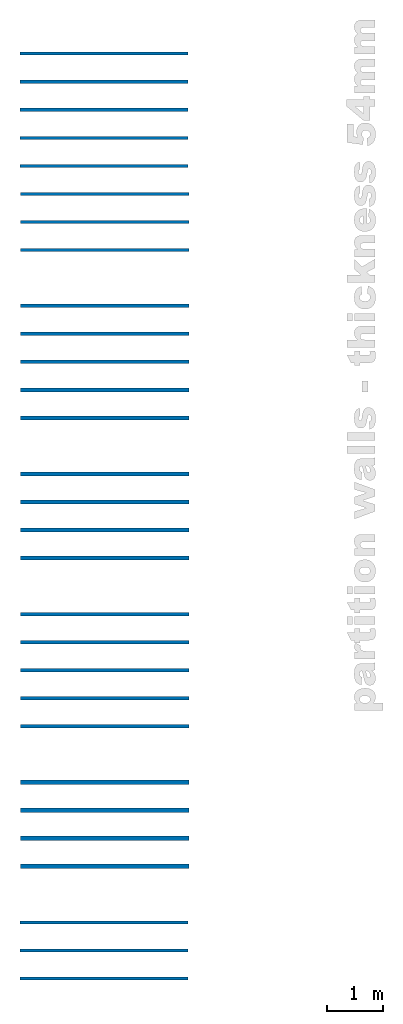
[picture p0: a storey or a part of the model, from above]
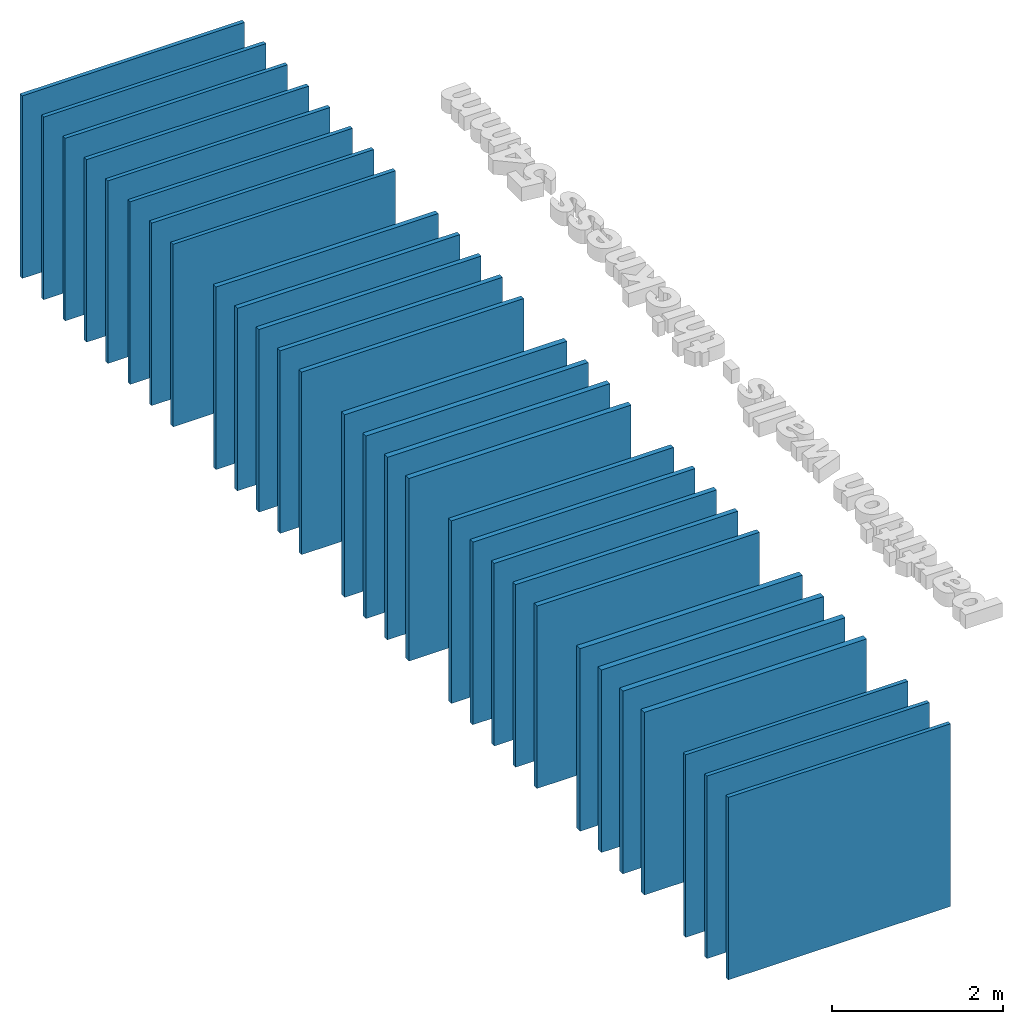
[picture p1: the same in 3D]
Properties of the parts of a building model (IFC2X3)

# File
Description: ViewDefinition [CoordinationView]
File name: 2344
Time: 2015-08-26T14:51:35
Written by: The EXPRESS Data Manager Version 5.02.0100.07 : 28 Aug 2013
Made in: 20140223_1515(x64) - Exporter 2015.0.2014.0223 - Default UI
Comment: STEP Physical File produced by: The EXPRESS Data Manager Version 5.02.0100.07 : 28 Aug 2013 * Module: EDMstepFileFactory/EDMstandAlone * Creation date: Wed Aug 26 14:51:35 2015 * Host: WKS-037 * Database: C:\Users\Alfons\AppData\Local\Temp\{7DC093A0-7D50-469D-A9C3-01EB25B16758}\ifc * Database version: 5507 * Database creation date: Wed Aug 26 14:51:34 2015 * Schema: IFC2X3 * Model: DataRepository.ifc * Model creation date: Wed Aug 26 14:51:34 2015 * Header model: DataRepository.ifc_HeaderModel * Header model creation date: Wed Aug 26 14:51:34 2015 * EDMuser: sdai-user * EDMgroup: sdai-group * License ID and type: 5605 : Permanent license. Expiry date: * EDMstepFileFactory options: 020000

# IfcProject, 2344
LongName: Project Name; Phase: DO

# IfcSite, Default
RefLatitude: 42, 21, 30, 344238; RefLongitude: -71, -3, -35, -194702; RefElevation: 0 mm
Other - Category: Project Information; Client Name: Owner; Project Address: Enter address here; Project Issue Date: Issue Date; Project Name: Project Name; Project Number: 2344; Project Status: DO

# IfcBuilding
Pset_BuildingCommon - NumberOfStoreys: 1
Other - Category: Project Information; Client Name: Owner; Project Address: Enter address here; Project Issue Date: Issue Date; Project Name: Project Name; Project Number: 2344; Project Status: DO

# IfcBuildingStorey, faay_bottom_view_color
LongName: faay_bottom_view_color; Elevation: 0 mm
Constraints - Elevation: 0 mm; Elevation Base: Project Base Point
Dimensions - Computation Height: 0 mm
Identity Data - Structural: no; Building Story: yes; Name: faay_bottom_view_color; Type Name: 8mm Head
Other - Category: Levels; Family: Level: 8mm Head; Family and Type: Level: 8mm Head; Type: Level: 8mm Head; Type Id: Level: 8mm Head; Family Name: Level
Graphics - Color: 0; Line Pattern: Centre; Line Weight: 1; Symbol: M_Level Head - Circle: M_Level Head - Circle; Symbol at End 1 Default: no; Symbol at End 2 Default: yes

# IfcBuildingElementProxy: Model Text:500 Arial Black
In: faay_bottom_view_color
Pset_BuildingElementProxyCommon - Reference: 500 Arial Black
Constraints - Work Plane: Level : faay_bottom_view_color
Dimensions - Depth: 200 mm
Graphics - Horizontal Align: Right; Text: partition walls - thickness 54mm
Identity Data - Subcategory: Generic Models; Type Name: 500 Arial Black
Other - Category: Generic Models; Family: Model Text: 500 Arial Black; Family and Type: Model Text: 500 Arial Black; Type: Model Text: 500 Arial Black; Type Id: Model Text: 500 Arial Black; Family Name: Model Text
Phasing - Phase Created: New Construction
Text - Bold: no; Italic: no; Text Font: Arial Black; Text Size: 500 mm

# IfcWallStandardCase: Basic Wall:Faay_22_RV54_, Basic Wall:Faay_22_RV54_:177242
In: faay_bottom_view_color
Type - PredefinedType: STANDARD; Material: faay_Rigidur 10 mm, faay_flax 34 mm, faay_Rigidur 10 mm
Type - Analytical Properties - Roughness: 1; Absorptance: 0.1
Type - Construction - Function: Exterior; Wrapping at Inserts: Do not wrap; Width: 54 mm
Type - Graphics - Coarse Scale Fill Color: 0
Type - Identity Data - Manufacturer: Faay Vianen B.V.; Model: Faay_22_RV54_; Type Name: Faay_22_RV54_; URL: http://http://www.faay.nl
Type - Other - Category: Walls; Family Name: Basic Wall
Type - Text - faay_avarage_labour_time_(mh/m2): 0.20; faay_fire_resistance_rating: >45 min.WBDBO; faay_heat_insulation_(Rc): 0.49; faay_sound_insulation_(DnTak): 26; faay_sound_insulation_(Rw): 27; faay_weight_(kg/m2): 23.85
Constraints - Base Constraint: Level: faay_bottom_view_color; Base Extension Distance: 0 mm; Base is Attached: no; Base Offset: 0 mm; Location Line: Wall Centerline; Related to Mass: no; Room Bounding: yes; Top Extension Distance: 0 mm; Top is Attached: no; Top Offset: 0 mm; Unconnected Height: 2605 mm
Dimensions - Area: 7.815 m2; Length: 3000 mm; Volume: 0.42201 m3
Other - Family: Basic Wall: Faay_22_RV54_; Family and Type: Basic Wall: Faay_22_RV54_; Type: Basic Wall: Faay_22_RV54_; Type Id: Basic Wall: Faay_22_RV54_
Phasing - Phase Created: New Construction
Structural - Enable Analytical Model: no; Structural: no; Structural Usage: Non-bearing
Pset_WallCommon - LoadBearing: no; ExtendToStructure: no; IsExternal: yes; Reference: Faay_22_RV54_
Pset_ManufacturerTypeInformation - Manufacturer: Faay Vianen B.V.

# IfcWallStandardCase: Basic Wall:Faay_22_SP54_, Basic Wall:Faay_22_SP54_:177233
In: faay_bottom_view_color
Type - PredefinedType: STANDARD; Material: faay_chipboard 10 mm, faay_flax 34 mm, faay_chipboard 10 mm
Type - Analytical Properties - Roughness: 1; Absorptance: 0.1
Type - Construction - Function: Exterior; Wrapping at Inserts: Do not wrap; Width: 54 mm
Type - Graphics - Coarse Scale Fill Color: 0
Type - Identity Data - Manufacturer: Faay Vianen B.V.; Model: Faay_22_SP54_; Type Name: Faay_22_SP54_; URL: http://http://www.faay.nl
Type - Other - Category: Walls; Family Name: Basic Wall
Type - Text - faay_avarage_labour_time_(mh/m2): 0.20; faay_fire_resistance_rating: <20 min.WBDBO; faay_heat_insulation_(Rc): 0.49; faay_sound_insulation_(DnTak): 24; faay_sound_insulation_(Rw): 27; faay_weight_(kg/m2): 23.85
Constraints - Base Constraint: Level: faay_bottom_view_color; Base Extension Distance: 0 mm; Base is Attached: no; Base Offset: 0 mm; Location Line: Wall Centerline; Related to Mass: no; Room Bounding: yes; Top Extension Distance: 0 mm; Top is Attached: no; Top Offset: 0 mm; Unconnected Height: 2605 mm
Dimensions - Area: 7.815 m2; Length: 3000 mm; Volume: 0.42201 m3
Other - Family: Basic Wall: Faay_22_SP54_; Family and Type: Basic Wall: Faay_22_SP54_; Type: Basic Wall: Faay_22_SP54_; Type Id: Basic Wall: Faay_22_SP54_
Phasing - Phase Created: New Construction
Structural - Enable Analytical Model: no; Structural: no; Structural Usage: Non-bearing
Pset_WallCommon - LoadBearing: no; ExtendToStructure: no; IsExternal: yes; Reference: Faay_22_SP54_
Pset_ManufacturerTypeInformation - Manufacturer: Faay Vianen B.V.

# IfcWallStandardCase: Basic Wall:Faay_22_SP54_Fo, Basic Wall:Faay_22_SP54_Fo:177236
In: faay_bottom_view_color
Type - PredefinedType: STANDARD; Material: faay_chipboard 10 mm, faay_flax 34 mm, faay_chipboard 10 mm
Type - Analytical Properties - Roughness: 1; Absorptance: 0.1
Type - Construction - Function: Exterior; Wrapping at Inserts: Do not wrap; Width: 54 mm
Type - Graphics - Coarse Scale Fill Color: 0
Type - Identity Data - Manufacturer: Faay Vianen B.V.; Model: Faay_22_SP54_F; Type Name: Faay_22_SP54_Fo; URL: http://http://www.faay.nl
Type - Other - Category: Walls; Family Name: Basic Wall
Type - Text - faay_avarage_labour_time_(mh/m2): 0.20; faay_fire_resistance_rating: <20 min.WBDBO; faay_heat_insulation_(Rc): 0.49; faay_sound_insulation_(DnTak): 24; faay_sound_insulation_(Rw): 27; faay_weight_(kg/m2): 23.85
Constraints - Base Constraint: Level: faay_bottom_view_color; Base Extension Distance: 0 mm; Base is Attached: no; Base Offset: 0 mm; Location Line: Wall Centerline; Related to Mass: no; Room Bounding: yes; Top Extension Distance: 0 mm; Top is Attached: no; Top Offset: 0 mm; Unconnected Height: 2605 mm
Dimensions - Area: 7.815 m2; Length: 3000 mm; Volume: 0.42201 m3
Other - Family: Basic Wall: Faay_22_SP54_Fo; Family and Type: Basic Wall: Faay_22_SP54_Fo; Type: Basic Wall: Faay_22_SP54_Fo; Type Id: Basic Wall: Faay_22_SP54_Fo
Phasing - Phase Created: New Construction
Structural - Enable Analytical Model: no; Structural: no; Structural Usage: Non-bearing
Pset_WallCommon - LoadBearing: no; ExtendToStructure: no; IsExternal: yes; Reference: Faay_22_SP54_Fo
Pset_ManufacturerTypeInformation - Manufacturer: Faay Vianen B.V.

# IfcWallStandardCase: Basic Wall:Faay_22_VP54_, Basic Wall:Faay_22_VP54_:177173
In: faay_bottom_view_color
Type - PredefinedType: STANDARD; Material: faay_gypsum 10 mm, faay_flax 34 mm, faay_gypsum 10 mm
Type - Analytical Properties - Roughness: 1; Absorptance: 0.1
Type - Construction - Function: Exterior; Wrapping at Inserts: Do not wrap; Width: 54 mm
Type - Graphics - Coarse Scale Fill Color: 7013078
Type - Identity Data - Manufacturer: Faay Vianen B.V.; Model: Faay_22_VP54_; Type Name: Faay_22_VP54_; URL: http://http://www.faay.nl
Type - Other - Category: Walls; Family Name: Basic Wall
Type - Text - faay_avarage_labour_time_(mh/m2): 0.20; faay_fire_resistance_rating: EI30; faay_heat_insulation_(Rc): 0.42; faay_sound_insulation_(DnTak): 29; faay_sound_insulation_(Rw): 30; faay_weight_(kg/m2): 38.12
Constraints - Base Constraint: Level: faay_bottom_view_color; Base Extension Distance: 0 mm; Base is Attached: no; Base Offset: 0 mm; Location Line: Wall Centerline; Related to Mass: no; Room Bounding: yes; Top Extension Distance: 0 mm; Top is Attached: no; Top Offset: 0 mm; Unconnected Height: 2605 mm
Dimensions - Area: 7.815 m2; Length: 3000 mm; Volume: 0.42201 m3
Other - Family: Basic Wall: Faay_22_VP54_; Family and Type: Basic Wall: Faay_22_VP54_; Type: Basic Wall: Faay_22_VP54_; Type Id: Basic Wall: Faay_22_VP54_
Phasing - Phase Created: New Construction
Structural - Enable Analytical Model: no; Structural: no; Structural Usage: Non-bearing
Pset_WallCommon - LoadBearing: no; ExtendToStructure: no; IsExternal: yes; Reference: Faay_22_VP54_
Pset_ManufacturerTypeInformation - Manufacturer: Faay Vianen B.V.

# IfcWallStandardCase: Basic Wall:Faay_22_VP54_10_1_B, Basic Wall:Faay_22_VP54_10_1_B:822858
In: faay_bottom_view_color
Type - PredefinedType: STANDARD; Material: faay_gypsum 10 mm, faay_gypsum 10 mm, faay_flax 34 mm, faay_gypsum 10 mm
Type - Analytical Properties - Roughness: 1; Absorptance: 0.1
Type - Construction - Function: Exterior; Wrapping at Inserts: Do not wrap; Width: 64 mm
Type - Graphics - Coarse Scale Fill Color: 0
Type - Identity Data - Manufacturer: Faay Vianen B.V.; Model: Faay_22_VP54_10_1; Type Name: Faay_22_VP54_10_1_B; URL: http://http://www.faay.nl
Type - Other - Category: Walls; Family Name: Basic Wall
Type - Text - faay_avarage_labour_time_(mh/m2): 0.33; faay_fire_resistance_rating: >60 min. WBDBO; faay_heat_insulation_(Rc): 0.45; faay_sound_insulation_(DnTak): 34; faay_sound_insulation_(Rw): 35; faay_weight_(kg/m2): 36.12
Constraints - Base Constraint: Level: faay_bottom_view_color; Base Extension Distance: 0 mm; Base is Attached: no; Base Offset: 0 mm; Location Line: Wall Centerline; Related to Mass: no; Room Bounding: yes; Top Extension Distance: 0 mm; Top is Attached: no; Top Offset: 0 mm; Unconnected Height: 2605 mm
Dimensions - Area: 7.815 m2; Length: 3000 mm; Volume: 0.50016 m3
Other - Family: Basic Wall: Faay_22_VP54_10_1_B; Family and Type: Basic Wall: Faay_22_VP54_10_1_B; Type: Basic Wall: Faay_22_VP54_10_1_B; Type Id: Basic Wall: Faay_22_VP54_10_1_B
Phasing - Phase Created: New Construction
Structural - Enable Analytical Model: no; Structural: no; Structural Usage: Non-bearing
Pset_WallCommon - LoadBearing: no; ExtendToStructure: no; IsExternal: yes; Reference: Faay_22_VP54_10_1_B
Pset_ManufacturerTypeInformation - Manufacturer: Faay Vianen B.V.

# IfcWallStandardCase: Basic Wall:Faay_22_VP54_10_1_F, Basic Wall:Faay_22_VP54_10_1_F:177185
In: faay_bottom_view_color
Type - PredefinedType: STANDARD; Material: faay_gypsum 10 mm, faay_flax 34 mm, faay_gypsum 10 mm, faay_gypsum 10 mm
Type - Analytical Properties - Roughness: 1; Absorptance: 0.1
Type - Construction - Function: Exterior; Wrapping at Inserts: Do not wrap; Width: 64 mm
Type - Graphics - Coarse Scale Fill Color: 0
Type - Identity Data - Manufacturer: Faay Vianen B.V.; Model: Faay_22_VP54_10_1; Type Name: Faay_22_VP54_10_1_F; URL: http://http://www.faay.nl
Type - Other - Category: Walls; Family Name: Basic Wall
Type - Text - faay_avarage_labour_time_(mh/m2): 0.33; faay_fire_resistance_rating: >60 min. WBDBO; faay_heat_insulation_(Rc): 0.45; faay_sound_insulation_(DnTak): 34; faay_sound_insulation_(Rw): 35; faay_weight_(kg/m2): 36.12
Constraints - Base Constraint: Level: faay_bottom_view_color; Base Extension Distance: 0 mm; Base is Attached: no; Base Offset: 0 mm; Location Line: Wall Centerline; Related to Mass: no; Room Bounding: yes; Top Extension Distance: 0 mm; Top is Attached: no; Top Offset: 0 mm; Unconnected Height: 2605 mm
Dimensions - Area: 7.815 m2; Length: 3000 mm; Volume: 0.50016 m3
Other - Family: Basic Wall: Faay_22_VP54_10_1_F; Family and Type: Basic Wall: Faay_22_VP54_10_1_F; Type: Basic Wall: Faay_22_VP54_10_1_F; Type Id: Basic Wall: Faay_22_VP54_10_1_F
Phasing - Phase Created: New Construction
Structural - Enable Analytical Model: no; Structural: no; Structural Usage: Non-bearing
Pset_WallCommon - LoadBearing: no; ExtendToStructure: no; IsExternal: yes; Reference: Faay_22_VP54_10_1_F
Pset_ManufacturerTypeInformation - Manufacturer: Faay Vianen B.V.

# IfcWallStandardCase: Basic Wall:Faay_22_VP54_10_1_WR1x_B, Basic Wall:Faay_22_VP54_10_1_WR1x_B:817365
In: faay_bottom_view_color
Type - PredefinedType: STANDARD; Material: faay_gypsum_WR 10 mm, faay_gypsum 10 mm, faay_flax 34 mm, faay_gypsum 10 mm
Type - Analytical Properties - Roughness: 1; Absorptance: 0.1
Type - Construction - Function: Exterior; Wrapping at Inserts: Do not wrap; Width: 64 mm
Type - Graphics - Coarse Scale Fill Color: 0
Type - Identity Data - Manufacturer: Faay Vianen B.V.; Model: Faay_22_VP54_10_1_WR1x_B; Type Name: Faay_22_VP54_10_1_WR1x_B; URL: http://http://www.faay.nl
Type - Other - Category: Walls; Family Name: Basic Wall
Type - Text - faay_avarage_labour_time_(mh/m2): 0.33; faay_fire_resistance_rating: >60 min. WBDBO; faay_heat_insulation_(Rc): 0.45; faay_sound_insulation_(DnTak): 34; faay_sound_insulation_(Rw): 35; faay_weight_(kg/m2): 36.12
Constraints - Base Constraint: Level: faay_bottom_view_color; Base Extension Distance: 0 mm; Base is Attached: no; Base Offset: 0 mm; Location Line: Wall Centerline; Related to Mass: no; Room Bounding: yes; Top Extension Distance: 0 mm; Top is Attached: no; Top Offset: 0 mm; Unconnected Height: 2605 mm
Dimensions - Area: 7.815 m2; Length: 3000 mm; Volume: 0.50016 m3
Other - Family: Basic Wall: Faay_22_VP54_10_1_WR1x_B; Family and Type: Basic Wall: Faay_22_VP54_10_1_WR1x_B; Type: Basic Wall: Faay_22_VP54_10_1_WR1x_B; Type Id: Basic Wall: Faay_22_VP54_10_1_WR1x_B
Phasing - Phase Created: New Construction
Structural - Enable Analytical Model: no; Structural: no; Structural Usage: Non-bearing
Pset_WallCommon - LoadBearing: no; ExtendToStructure: no; IsExternal: yes; Reference: Faay_22_VP54_10_1_WR1x_B
Pset_ManufacturerTypeInformation - Manufacturer: Faay Vianen B.V.

# IfcWallStandardCase: Basic Wall:Faay_22_VP54_10_1_WR1x_F, Basic Wall:Faay_22_VP54_10_1_WR1x_F:177184
In: faay_bottom_view_color
Type - PredefinedType: STANDARD; Material: faay_gypsum 10 mm, faay_flax 34 mm, faay_gypsum 10 mm, faay_gypsum_WR 10 mm
Type - Analytical Properties - Roughness: 1; Absorptance: 0.1
Type - Construction - Function: Exterior; Wrapping at Inserts: Do not wrap; Width: 64 mm
Type - Graphics - Coarse Scale Fill Color: 0
Type - Identity Data - Manufacturer: Faay Vianen B.V.; Model: Faay_22_VP54_10_1_WR1x_F; Type Name: Faay_22_VP54_10_1_WR1x_F; URL: http://http://www.faay.nl
Type - Other - Category: Walls; Family Name: Basic Wall
Type - Text - faay_avarage_labour_time_(mh/m2): 0.33; faay_fire_resistance_rating: >60 min. WBDBO; faay_heat_insulation_(Rc): 0.45; faay_sound_insulation_(DnTak): 34; faay_sound_insulation_(Rw): 35; faay_weight_(kg/m2): 36.12
Constraints - Base Constraint: Level: faay_bottom_view_color; Base Extension Distance: 0 mm; Base is Attached: no; Base Offset: 0 mm; Location Line: Wall Centerline; Related to Mass: no; Room Bounding: yes; Top Extension Distance: 0 mm; Top is Attached: no; Top Offset: 0 mm; Unconnected Height: 2605 mm
Dimensions - Area: 7.815 m2; Length: 3000 mm; Volume: 0.50016 m3
Other - Family: Basic Wall: Faay_22_VP54_10_1_WR1x_F; Family and Type: Basic Wall: Faay_22_VP54_10_1_WR1x_F; Type: Basic Wall: Faay_22_VP54_10_1_WR1x_F; Type Id: Basic Wall: Faay_22_VP54_10_1_WR1x_F
Phasing - Phase Created: New Construction
Structural - Enable Analytical Model: no; Structural: no; Structural Usage: Non-bearing
Pset_WallCommon - LoadBearing: no; ExtendToStructure: no; IsExternal: yes; Reference: Faay_22_VP54_10_1_WR1x_F
Pset_ManufacturerTypeInformation - Manufacturer: Faay Vianen B.V.

# IfcWallStandardCase: Basic Wall:Faay_22_VP54_10_1_WR2x, Basic Wall:Faay_22_VP54_10_1_WR2x:177183
In: faay_bottom_view_color
Type - PredefinedType: STANDARD; Material: faay_gypsum_WR 10 mm, faay_flax 34 mm, faay_gypsum 10 mm, faay_gypsum_WR 10 mm
Type - Analytical Properties - Roughness: 1; Absorptance: 0.1
Type - Construction - Function: Exterior; Wrapping at Inserts: Do not wrap; Width: 64 mm
Type - Graphics - Coarse Scale Fill Color: 0
Type - Identity Data - Manufacturer: Faay Vianen B.V.; Model: Faay_22_VP54_10_1_WR2x; Type Name: Faay_22_VP54_10_1_WR2x; URL: http://http://www.faay.nl
Type - Other - Category: Walls; Family Name: Basic Wall
Type - Text - faay_avarage_labour_time_(mh/m2): 0.33; faay_fire_resistance_rating: >60 min. WBDBO; faay_heat_insulation_(Rc): 0.45; faay_sound_insulation_(DnTak): 34; faay_sound_insulation_(Rw): 35; faay_weight_(kg/m2): 36.12
Constraints - Base Constraint: Level: faay_bottom_view_color; Base Extension Distance: 0 mm; Base is Attached: no; Base Offset: 0 mm; Location Line: Wall Centerline; Related to Mass: no; Room Bounding: yes; Top Extension Distance: 0 mm; Top is Attached: no; Top Offset: 0 mm; Unconnected Height: 2605 mm
Dimensions - Area: 7.815 m2; Length: 3000 mm; Volume: 0.50016 m3
Other - Family: Basic Wall: Faay_22_VP54_10_1_WR2x; Family and Type: Basic Wall: Faay_22_VP54_10_1_WR2x; Type: Basic Wall: Faay_22_VP54_10_1_WR2x; Type Id: Basic Wall: Faay_22_VP54_10_1_WR2x
Phasing - Phase Created: New Construction
Structural - Enable Analytical Model: no; Structural: no; Structural Usage: Non-bearing
Pset_WallCommon - LoadBearing: no; ExtendToStructure: no; IsExternal: yes; Reference: Faay_22_VP54_10_1_WR2x
Pset_ManufacturerTypeInformation - Manufacturer: Faay Vianen B.V.

# IfcWallStandardCase: Basic Wall:Faay_22_VP54_10_2_, Basic Wall:Faay_22_VP54_10_2_:177207
In: faay_bottom_view_color
Type - PredefinedType: STANDARD; Material: faay_gypsum 10 mm, faay_gypsum 10 mm, faay_flax 34 mm, faay_gypsum 10 mm, faay_gypsum 10 mm
Type - Analytical Properties - Roughness: 1; Absorptance: 0.1
Type - Construction - Function: Exterior; Wrapping at Inserts: Do not wrap; Width: 74 mm
Type - Graphics - Coarse Scale Fill Color: 0
Type - Identity Data - Manufacturer: Faay Vianen B.V.; Model: Faay_22_VP54_10_2; Type Name: Faay_22_VP54_10_2_; URL: http://http://www.faay.nl
Type - Other - Category: Walls; Family Name: Basic Wall
Type - Text - faay_avarage_labour_time_(mh/m2): 0.46; faay_fire_resistance_rating: >60 min. WBDBO; faay_heat_insulation_(Rc): 0.49; faay_sound_insulation_(DnTak): 35; faay_sound_insulation_(Rw): 36; faay_weight_(kg/m2): 44.12
Constraints - Base Constraint: Level: faay_bottom_view_color; Base Extension Distance: 0 mm; Base is Attached: no; Base Offset: 0 mm; Location Line: Wall Centerline; Related to Mass: no; Room Bounding: yes; Top Extension Distance: 0 mm; Top is Attached: no; Top Offset: 0 mm; Unconnected Height: 2605 mm
Dimensions - Area: 7.815 m2; Length: 3000 mm; Volume: 0.57831 m3
Other - Family: Basic Wall: Faay_22_VP54_10_2_; Family and Type: Basic Wall: Faay_22_VP54_10_2_; Type: Basic Wall: Faay_22_VP54_10_2_; Type Id: Basic Wall: Faay_22_VP54_10_2_
Phasing - Phase Created: New Construction
Structural - Enable Analytical Model: no; Structural: no; Structural Usage: Non-bearing
Pset_WallCommon - LoadBearing: no; ExtendToStructure: no; IsExternal: yes; Reference: Faay_22_VP54_10_2_
Pset_ManufacturerTypeInformation - Manufacturer: Faay Vianen B.V.

# IfcWallStandardCase: Basic Wall:Faay_22_VP54_10_2_WR1x_B, Basic Wall:Faay_22_VP54_10_2_WR1x_B:177206
In: faay_bottom_view_color
Type - PredefinedType: STANDARD; Material: faay_gypsum_WR 10 mm, faay_gypsum 10 mm, faay_flax 34 mm, faay_gypsum 10 mm, faay_gypsum 10 mm
Type - Analytical Properties - Roughness: 1; Absorptance: 0.1
Type - Construction - Function: Exterior; Wrapping at Inserts: Do not wrap; Width: 74 mm
Type - Graphics - Coarse Scale Fill Color: 0
Type - Identity Data - Manufacturer: Faay Vianen B.V.; Model: Faay_22_VP54_10_2_WR1x_B; Type Name: Faay_22_VP54_10_2_WR1x_B; URL: http://http://www.faay.nl
Type - Other - Category: Walls; Family Name: Basic Wall
Type - Text - faay_avarage_labour_time_(mh/m2): 0.46; faay_fire_resistance_rating: >60 min. WBDBO; faay_heat_insulation_(Rc): 0.49; faay_sound_insulation_(DnTak): 35; faay_sound_insulation_(Rw): 36; faay_weight_(kg/m2): 44.12
Constraints - Base Constraint: Level: faay_bottom_view_color; Base Extension Distance: 0 mm; Base is Attached: no; Base Offset: 0 mm; Location Line: Wall Centerline; Related to Mass: no; Room Bounding: yes; Top Extension Distance: 0 mm; Top is Attached: no; Top Offset: 0 mm; Unconnected Height: 2605 mm
Dimensions - Area: 7.815 m2; Length: 3000 mm; Volume: 0.57831 m3
Other - Family: Basic Wall: Faay_22_VP54_10_2_WR1x_B; Family and Type: Basic Wall: Faay_22_VP54_10_2_WR1x_B; Type: Basic Wall: Faay_22_VP54_10_2_WR1x_B; Type Id: Basic Wall: Faay_22_VP54_10_2_WR1x_B
Phasing - Phase Created: New Construction
Structural - Enable Analytical Model: no; Structural: no; Structural Usage: Non-bearing
Pset_WallCommon - LoadBearing: no; ExtendToStructure: no; IsExternal: yes; Reference: Faay_22_VP54_10_2_WR1x_B
Pset_ManufacturerTypeInformation - Manufacturer: Faay Vianen B.V.

# IfcWallStandardCase: Basic Wall:Faay_22_VP54_10_2_WR1x_F, Basic Wall:Faay_22_VP54_10_2_WR1x_F:817162
In: faay_bottom_view_color
Type - PredefinedType: STANDARD; Material: faay_gypsum 10 mm, faay_gypsum 10 mm, faay_flax 34 mm, faay_gypsum 10 mm, faay_gypsum_WR 10 mm
Type - Analytical Properties - Roughness: 1; Absorptance: 0.1
Type - Construction - Function: Exterior; Wrapping at Inserts: Do not wrap; Width: 74 mm
Type - Graphics - Coarse Scale Fill Color: 0
Type - Identity Data - Manufacturer: Faay Vianen B.V.; Model: Faay_22_VP54_10_2_WR1x_F; Type Name: Faay_22_VP54_10_2_WR1x_F; URL: http://http://www.faay.nl
Type - Other - Category: Walls; Family Name: Basic Wall
Type - Text - faay_avarage_labour_time_(mh/m2): 0.46; faay_fire_resistance_rating: >60 min. WBDBO; faay_heat_insulation_(Rc): 0.49; faay_sound_insulation_(DnTak): 35; faay_sound_insulation_(Rw): 36; faay_weight_(kg/m2): 44.12
Constraints - Base Constraint: Level: faay_bottom_view_color; Base Extension Distance: 0 mm; Base is Attached: no; Base Offset: 0 mm; Location Line: Wall Centerline; Related to Mass: no; Room Bounding: yes; Top Extension Distance: 0 mm; Top is Attached: no; Top Offset: 0 mm; Unconnected Height: 2605 mm
Dimensions - Area: 7.815 m2; Length: 3000 mm; Volume: 0.57831 m3
Other - Family: Basic Wall: Faay_22_VP54_10_2_WR1x_F; Family and Type: Basic Wall: Faay_22_VP54_10_2_WR1x_F; Type: Basic Wall: Faay_22_VP54_10_2_WR1x_F; Type Id: Basic Wall: Faay_22_VP54_10_2_WR1x_F
Phasing - Phase Created: New Construction
Structural - Enable Analytical Model: no; Structural: no; Structural Usage: Non-bearing
Pset_WallCommon - LoadBearing: no; ExtendToStructure: no; IsExternal: yes; Reference: Faay_22_VP54_10_2_WR1x_F
Pset_ManufacturerTypeInformation - Manufacturer: Faay Vianen B.V.

# IfcWallStandardCase: Basic Wall:Faay_22_VP54_10_2_WR2x, Basic Wall:Faay_22_VP54_10_2_WR2x:177212
In: faay_bottom_view_color
Type - PredefinedType: STANDARD; Material: faay_gypsum_WR 10 mm, faay_gypsum 10 mm, faay_flax 34 mm, faay_gypsum 10 mm, faay_gypsum_WR 10 mm
Type - Analytical Properties - Roughness: 1; Absorptance: 0.1
Type - Construction - Function: Exterior; Wrapping at Inserts: Do not wrap; Width: 74 mm
Type - Graphics - Coarse Scale Fill Color: 0
Type - Identity Data - Manufacturer: Faay Vianen B.V.; Model: Faay_22_VP54_10_2_WR2x; Type Name: Faay_22_VP54_10_2_WR2x; URL: http://http://www.faay.nl
Type - Other - Category: Walls; Family Name: Basic Wall
Type - Text - faay_avarage_labour_time_(mh/m2): 0.46; faay_fire_resistance_rating: >60 min. WBDBO; faay_heat_insulation_(Rc): 0.49; faay_sound_insulation_(DnTak): 35; faay_sound_insulation_(Rw): 36; faay_weight_(kg/m2): 44.12
Constraints - Base Constraint: Level: faay_bottom_view_color; Base Extension Distance: 0 mm; Base is Attached: no; Base Offset: 0 mm; Location Line: Wall Centerline; Related to Mass: no; Room Bounding: yes; Top Extension Distance: 0 mm; Top is Attached: no; Top Offset: 0 mm; Unconnected Height: 2605 mm
Dimensions - Area: 7.815 m2; Length: 3000 mm; Volume: 0.57831 m3
Other - Family: Basic Wall: Faay_22_VP54_10_2_WR2x; Family and Type: Basic Wall: Faay_22_VP54_10_2_WR2x; Type: Basic Wall: Faay_22_VP54_10_2_WR2x; Type Id: Basic Wall: Faay_22_VP54_10_2_WR2x
Phasing - Phase Created: New Construction
Structural - Enable Analytical Model: no; Structural: no; Structural Usage: Non-bearing
Pset_WallCommon - LoadBearing: no; ExtendToStructure: no; IsExternal: yes; Reference: Faay_22_VP54_10_2_WR2x
Pset_ManufacturerTypeInformation - Manufacturer: Faay Vianen B.V.

# IfcWallStandardCase: Basic Wall:Faay_22_VP54_12.5_1_B, Basic Wall:Faay_22_VP54_12.5_1_B:825457
In: faay_bottom_view_color
Type - PredefinedType: STANDARD; Material: faay_gypsum 12.5 mm, faay_gypsum 10 mm, faay_flax 34 mm, faay_gypsum 10 mm
Type - Analytical Properties - Roughness: 1; Absorptance: 0.1
Type - Construction - Function: Exterior; Wrapping at Inserts: Do not wrap; Width: 66.5 mm
Type - Graphics - Coarse Scale Fill Color: 0
Type - Identity Data - Manufacturer: Faay Vianen B.V.; Model: Faay_22_VP54_12.5_1; Type Name: Faay_22_VP54_12.5_1_B; URL: http://http://www.faay.nl
Type - Other - Category: Walls; Family Name: Basic Wall
Type - Text - faay_avarage_labour_time_(mh/m2): 0.33; faay_fire_resistance_rating: >60 min. WBDBO; faay_heat_insulation_(Rc): 0.45; faay_sound_insulation_(DnTak): 34; faay_sound_insulation_(Rw): 35; faay_weight_(kg/m2): 38.92
Constraints - Base Constraint: Level: faay_bottom_view_color; Base Extension Distance: 0 mm; Base is Attached: no; Base Offset: 0 mm; Location Line: Wall Centerline; Related to Mass: no; Room Bounding: yes; Top Extension Distance: 0 mm; Top is Attached: no; Top Offset: 0 mm; Unconnected Height: 2605 mm
Dimensions - Area: 7.815 m2; Length: 3000 mm; Volume: 0.519698 m3
Other - Family: Basic Wall: Faay_22_VP54_12.5_1_B; Family and Type: Basic Wall: Faay_22_VP54_12.5_1_B; Type: Basic Wall: Faay_22_VP54_12.5_1_B; Type Id: Basic Wall: Faay_22_VP54_12.5_1_B
Phasing - Phase Created: New Construction
Structural - Enable Analytical Model: no; Structural: no; Structural Usage: Non-bearing
Pset_WallCommon - LoadBearing: no; ExtendToStructure: no; IsExternal: yes; Reference: Faay_22_VP54_12.5_1_B
Pset_ManufacturerTypeInformation - Manufacturer: Faay Vianen B.V.

# IfcWallStandardCase: Basic Wall:Faay_22_VP54_12.5_1_F, Basic Wall:Faay_22_VP54_12.5_1_F:177217
In: faay_bottom_view_color
Type - PredefinedType: STANDARD; Material: faay_gypsum 10 mm, faay_flax 34 mm, faay_gypsum 10 mm, faay_gypsum 12.5 mm
Type - Analytical Properties - Roughness: 1; Absorptance: 0.1
Type - Construction - Function: Exterior; Wrapping at Inserts: Do not wrap; Width: 66.5 mm
Type - Graphics - Coarse Scale Fill Color: 0
Type - Identity Data - Manufacturer: Faay Vianen B.V.; Model: Faay_22_VP54_12.5_1; Type Name: Faay_22_VP54_12.5_1_F; URL: http://http://www.faay.nl
Type - Other - Category: Walls; Family Name: Basic Wall
Type - Text - faay_avarage_labour_time_(mh/m2): 0.33; faay_fire_resistance_rating: >60 min. WBDBO; faay_heat_insulation_(Rc): 0.45; faay_sound_insulation_(DnTak): 34; faay_sound_insulation_(Rw): 35; faay_weight_(kg/m2): 38.92
Constraints - Base Constraint: Level: faay_bottom_view_color; Base Extension Distance: 0 mm; Base is Attached: no; Base Offset: 0 mm; Location Line: Wall Centerline; Related to Mass: no; Room Bounding: yes; Top Extension Distance: 0 mm; Top is Attached: no; Top Offset: 0 mm; Unconnected Height: 2605 mm
Dimensions - Area: 7.815 m2; Length: 3000 mm; Volume: 0.519698 m3
Other - Family: Basic Wall: Faay_22_VP54_12.5_1_F; Family and Type: Basic Wall: Faay_22_VP54_12.5_1_F; Type: Basic Wall: Faay_22_VP54_12.5_1_F; Type Id: Basic Wall: Faay_22_VP54_12.5_1_F
Phasing - Phase Created: New Construction
Structural - Enable Analytical Model: no; Structural: no; Structural Usage: Non-bearing
Pset_WallCommon - LoadBearing: no; ExtendToStructure: no; IsExternal: yes; Reference: Faay_22_VP54_12.5_1_F
Pset_ManufacturerTypeInformation - Manufacturer: Faay Vianen B.V.

# IfcWallStandardCase: Basic Wall:Faay_22_VP54_12.5_1_WR1x_B, Basic Wall:Faay_22_VP54_12.5_1_WR1x_B:177216
In: faay_bottom_view_color
Type - PredefinedType: STANDARD; Material: faay_gypsum_WR 10 mm, faay_flax 34 mm, faay_gypsum 10 mm, faay_gypsum 12.5 mm
Type - Analytical Properties - Roughness: 1; Absorptance: 0.1
Type - Construction - Function: Exterior; Wrapping at Inserts: Do not wrap; Width: 66.5 mm
Type - Graphics - Coarse Scale Fill Color: 0
Type - Identity Data - Manufacturer: Faay Vianen B.V.; Model: Faay_22_VP54_12.5_1_WR1x_B; Type Name: Faay_22_VP54_12.5_1_WR1x_B; URL: http://http://www.faay.nl
Type - Other - Category: Walls; Family Name: Basic Wall
Type - Text - faay_avarage_labour_time_(mh/m2): 0.33; faay_fire_resistance_rating: >60 min. WBDBO; faay_heat_insulation_(Rc): 0.45; faay_sound_insulation_(DnTak): 34; faay_sound_insulation_(Rw): 35; faay_weight_(kg/m2): 38.92
Constraints - Base Constraint: Level: faay_bottom_view_color; Base Extension Distance: 0 mm; Base is Attached: no; Base Offset: 0 mm; Location Line: Wall Centerline; Related to Mass: no; Room Bounding: yes; Top Extension Distance: 0 mm; Top is Attached: no; Top Offset: 0 mm; Unconnected Height: 2605 mm
Dimensions - Area: 7.815 m2; Length: 3000 mm; Volume: 0.519697 m3
Other - Family: Basic Wall: Faay_22_VP54_12.5_1_WR1x_B; Family and Type: Basic Wall: Faay_22_VP54_12.5_1_WR1x_B; Type: Basic Wall: Faay_22_VP54_12.5_1_WR1x_B; Type Id: Basic Wall: Faay_22_VP54_12.5_1_WR1x_B
Phasing - Phase Created: New Construction
Structural - Enable Analytical Model: no; Structural: no; Structural Usage: Non-bearing
Pset_WallCommon - LoadBearing: no; ExtendToStructure: no; IsExternal: yes; Reference: Faay_22_VP54_12.5_1_WR1x_B
Pset_ManufacturerTypeInformation - Manufacturer: Faay Vianen B.V.

# IfcWallStandardCase: Basic Wall:Faay_22_VP54_12.5_1_WR1x_F, Basic Wall:Faay_22_VP54_12.5_1_WR1x_F:817574
In: faay_bottom_view_color
Type - PredefinedType: STANDARD; Material: faay_gypsum 12.5 mm, faay_gypsum 10 mm, faay_flax 34 mm, faay_gypsum_WR 10 mm
Type - Analytical Properties - Roughness: 1; Absorptance: 0.1
Type - Construction - Function: Exterior; Wrapping at Inserts: Do not wrap; Width: 66.5 mm
Type - Graphics - Coarse Scale Fill Color: 0
Type - Identity Data - Manufacturer: Faay Vianen B.V.; Model: Faay_22_VP54_12.5_1_WR1x_F; Type Name: Faay_22_VP54_12.5_1_WR1x_F; URL: http://http://www.faay.nl
Type - Other - Category: Walls; Family Name: Basic Wall
Type - Text - faay_avarage_labour_time_(mh/m2): 0.33; faay_fire_resistance_rating: >60 min. WBDBO; faay_heat_insulation_(Rc): 0.45; faay_sound_insulation_(DnTak): 34; faay_sound_insulation_(Rw): 35; faay_weight_(kg/m2): 38.92
Constraints - Base Constraint: Level: faay_bottom_view_color; Base Extension Distance: 0 mm; Base is Attached: no; Base Offset: 0 mm; Location Line: Wall Centerline; Related to Mass: no; Room Bounding: yes; Top Extension Distance: 0 mm; Top is Attached: no; Top Offset: 0 mm; Unconnected Height: 2605 mm
Dimensions - Area: 7.815 m2; Length: 3000 mm; Volume: 0.519697 m3
Other - Family: Basic Wall: Faay_22_VP54_12.5_1_WR1x_F; Family and Type: Basic Wall: Faay_22_VP54_12.5_1_WR1x_F; Type: Basic Wall: Faay_22_VP54_12.5_1_WR1x_F; Type Id: Basic Wall: Faay_22_VP54_12.5_1_WR1x_F
Phasing - Phase Created: New Construction
Structural - Enable Analytical Model: no; Structural: no; Structural Usage: Non-bearing
Pset_WallCommon - LoadBearing: no; ExtendToStructure: no; IsExternal: yes; Reference: Faay_22_VP54_12.5_1_WR1x_F
Pset_ManufacturerTypeInformation - Manufacturer: Faay Vianen B.V.

# IfcWallStandardCase: Basic Wall:Faay_22_VP54_12.5_1_WR2x, Basic Wall:Faay_22_VP54_12.5_1_WR2x:177215
In: faay_bottom_view_color
Type - PredefinedType: STANDARD; Material: faay_gypsum_WR 10 mm, faay_flax 34 mm, faay_gypsum 10 mm, faay_gypsum_WR 12.5 mm
Type - Analytical Properties - Roughness: 1; Absorptance: 0.1
Type - Construction - Function: Exterior; Wrapping at Inserts: Do not wrap; Width: 66.5 mm
Type - Graphics - Coarse Scale Fill Color: 0
Type - Identity Data - Manufacturer: Faay Vianen B.V.; Model: Faay_22_VP54_12.5_1_WR2x; Type Name: Faay_22_VP54_12.5_1_WR2x; URL: http://http://www.faay.nl
Type - Other - Category: Walls; Family Name: Basic Wall
Type - Text - faay_avarage_labour_time_(mh/m2): 0.33; faay_fire_resistance_rating: >60 min. WBDBO; faay_heat_insulation_(Rc): 0.45; faay_sound_insulation_(DnTak): 34; faay_sound_insulation_(Rw): 35; faay_weight_(kg/m2): 38.92
Constraints - Base Constraint: Level: faay_bottom_view_color; Base Extension Distance: 0 mm; Base is Attached: no; Base Offset: 0 mm; Location Line: Wall Centerline; Related to Mass: no; Room Bounding: yes; Top Extension Distance: 0 mm; Top is Attached: no; Top Offset: 0 mm; Unconnected Height: 2605 mm
Dimensions - Area: 7.815 m2; Length: 3000 mm; Volume: 0.519697 m3
Other - Family: Basic Wall: Faay_22_VP54_12.5_1_WR2x; Family and Type: Basic Wall: Faay_22_VP54_12.5_1_WR2x; Type: Basic Wall: Faay_22_VP54_12.5_1_WR2x; Type Id: Basic Wall: Faay_22_VP54_12.5_1_WR2x
Phasing - Phase Created: New Construction
Structural - Enable Analytical Model: no; Structural: no; Structural Usage: Non-bearing
Pset_WallCommon - LoadBearing: no; ExtendToStructure: no; IsExternal: yes; Reference: Faay_22_VP54_12.5_1_WR2x
Pset_ManufacturerTypeInformation - Manufacturer: Faay Vianen B.V.

# IfcWallStandardCase: Basic Wall:Faay_22_VP54_12.5_2_, Basic Wall:Faay_22_VP54_12.5_2_:832891
In: faay_bottom_view_color
Type - PredefinedType: STANDARD; Material: faay_gypsum 12.5 mm, faay_gypsum 10 mm, faay_flax 34 mm, faay_gypsum 10 mm, faay_gypsum 12.5 mm
Type - Analytical Properties - Roughness: 1; Absorptance: 0.1
Type - Construction - Function: Exterior; Wrapping at Inserts: Do not wrap; Width: 79 mm
Type - Graphics - Coarse Scale Fill Color: 0
Type - Identity Data - Manufacturer: Faay Vianen B.V.; Model: Faay_22_VP54_12.5_2; Type Name: Faay_22_VP54_12.5_2_; URL: http://http://www.faay.nl
Type - Other - Category: Walls; Family Name: Basic Wall
Type - Text - faay_avarage_labour_time_(mh/m2): 0.46; faay_fire_resistance_rating: >60 min. WBDBO; faay_heat_insulation_(Rc): 0.65; faay_sound_insulation_(DnTak): 34; faay_sound_insulation_(Rw): 35; faay_weight_(kg/m2): 49.72
Constraints - Base Constraint: Level: faay_bottom_view_color; Base Extension Distance: 0 mm; Base is Attached: no; Base Offset: 0 mm; Location Line: Wall Centerline; Related to Mass: no; Room Bounding: yes; Top Extension Distance: 0 mm; Top is Attached: no; Top Offset: 0 mm; Unconnected Height: 2605 mm
Dimensions - Area: 7.815 m2; Length: 3000 mm; Volume: 0.617385 m3
Other - Family: Basic Wall: Faay_22_VP54_12.5_2_; Family and Type: Basic Wall: Faay_22_VP54_12.5_2_; Type: Basic Wall: Faay_22_VP54_12.5_2_; Type Id: Basic Wall: Faay_22_VP54_12.5_2_
Phasing - Phase Created: New Construction
Structural - Enable Analytical Model: no; Structural: no; Structural Usage: Non-bearing
Pset_WallCommon - LoadBearing: no; ExtendToStructure: no; IsExternal: yes; Reference: Faay_22_VP54_12.5_2_
Pset_ManufacturerTypeInformation - Manufacturer: Faay Vianen B.V.

# IfcWallStandardCase: Basic Wall:Faay_22_VP54_12.5_2_WR1x_B, Basic Wall:Faay_22_VP54_12.5_2_WR1x_B:832890
In: faay_bottom_view_color
Type - PredefinedType: STANDARD; Material: faay_gypsum_WR 12.5 mm, faay_gypsum 10 mm, faay_flax 34 mm, faay_gypsum 10 mm, faay_gypsum 12.5 mm
Type - Analytical Properties - Roughness: 1; Absorptance: 0.1
Type - Construction - Function: Exterior; Wrapping at Inserts: Do not wrap; Width: 79 mm
Type - Graphics - Coarse Scale Fill Color: 0
Type - Identity Data - Manufacturer: Faay Vianen B.V.; Model: Faay_22_VP54_12.5_2_WR1x_B; Type Name: Faay_22_VP54_12.5_2_WR1x_B; URL: http://http://www.faay.nl
Type - Other - Category: Walls; Family Name: Basic Wall
Type - Text - faay_avarage_labour_time_(mh/m2): 0.46; faay_fire_resistance_rating: >60 min. WBDBO; faay_heat_insulation_(Rc): 0.65; faay_sound_insulation_(DnTak): 34; faay_sound_insulation_(Rw): 35; faay_weight_(kg/m2): 49.72
Constraints - Base Constraint: Level: faay_bottom_view_color; Base Extension Distance: 0 mm; Base is Attached: no; Base Offset: 0 mm; Location Line: Wall Centerline; Related to Mass: no; Room Bounding: yes; Top Extension Distance: 0 mm; Top is Attached: no; Top Offset: 0 mm; Unconnected Height: 2605 mm
Dimensions - Area: 7.815 m2; Length: 3000 mm; Volume: 0.617385 m3
Other - Family: Basic Wall: Faay_22_VP54_12.5_2_WR1x_B; Family and Type: Basic Wall: Faay_22_VP54_12.5_2_WR1x_B; Type: Basic Wall: Faay_22_VP54_12.5_2_WR1x_B; Type Id: Basic Wall: Faay_22_VP54_12.5_2_WR1x_B
Phasing - Phase Created: New Construction
Structural - Enable Analytical Model: no; Structural: no; Structural Usage: Non-bearing
Pset_WallCommon - LoadBearing: no; ExtendToStructure: no; IsExternal: yes; Reference: Faay_22_VP54_12.5_2_WR1x_B
Pset_ManufacturerTypeInformation - Manufacturer: Faay Vianen B.V.

# IfcWallStandardCase: Basic Wall:Faay_22_VP54_12.5_2_WR1x_F, Basic Wall:Faay_22_VP54_12.5_2_WR1x_F:832896
In: faay_bottom_view_color
Type - PredefinedType: STANDARD; Material: faay_gypsum 12.5 mm, faay_gypsum 10 mm, faay_flax 34 mm, faay_gypsum 10 mm, faay_gypsum_WR 12.5 mm
Type - Analytical Properties - Roughness: 1; Absorptance: 0.1
Type - Construction - Function: Exterior; Wrapping at Inserts: Do not wrap; Width: 79 mm
Type - Graphics - Coarse Scale Fill Color: 0
Type - Identity Data - Manufacturer: Faay Vianen B.V.; Model: Faay_22_VP54_12.5_2_WR1x_F; Type Name: Faay_22_VP54_12.5_2_WR1x_F; URL: http://http://www.faay.nl
Type - Other - Category: Walls; Family Name: Basic Wall
Type - Text - faay_avarage_labour_time_(mh/m2): 0.46; faay_fire_resistance_rating: >60 min. WBDBO; faay_heat_insulation_(Rc): 0.65; faay_sound_insulation_(DnTak): 34; faay_sound_insulation_(Rw): 35; faay_weight_(kg/m2): 49.72
Constraints - Base Constraint: Level: faay_bottom_view_color; Base Extension Distance: 0 mm; Base is Attached: no; Base Offset: 0 mm; Location Line: Wall Centerline; Related to Mass: no; Room Bounding: yes; Top Extension Distance: 0 mm; Top is Attached: no; Top Offset: 0 mm; Unconnected Height: 2605 mm
Dimensions - Area: 7.815 m2; Length: 3000 mm; Volume: 0.617385 m3
Other - Family: Basic Wall: Faay_22_VP54_12.5_2_WR1x_F; Family and Type: Basic Wall: Faay_22_VP54_12.5_2_WR1x_F; Type: Basic Wall: Faay_22_VP54_12.5_2_WR1x_F; Type Id: Basic Wall: Faay_22_VP54_12.5_2_WR1x_F
Phasing - Phase Created: New Construction
Structural - Enable Analytical Model: no; Structural: no; Structural Usage: Non-bearing
Pset_WallCommon - LoadBearing: no; ExtendToStructure: no; IsExternal: yes; Reference: Faay_22_VP54_12.5_2_WR1x_F
Pset_ManufacturerTypeInformation - Manufacturer: Faay Vianen B.V.

# IfcWallStandardCase: Basic Wall:Faay_22_VP54_12.5_2_WR2x, Basic Wall:Faay_22_VP54_12.5_2_WR2x:832894
In: faay_bottom_view_color
Type - PredefinedType: STANDARD; Material: faay_gypsum_WR 12.5 mm, faay_gypsum 10 mm, faay_flax 34 mm, faay_gypsum 10 mm, faay_gypsum_WR 12.5 mm
Type - Analytical Properties - Roughness: 1; Absorptance: 0.1
Type - Construction - Function: Exterior; Wrapping at Inserts: Do not wrap; Width: 79 mm
Type - Graphics - Coarse Scale Fill Color: 0
Type - Identity Data - Manufacturer: Faay Vianen B.V.; Model: Faay_22_VP54_12.5_2_WR2x; Type Name: Faay_22_VP54_12.5_2_WR2x; URL: http://http://www.faay.nl
Type - Other - Category: Walls; Family Name: Basic Wall
Type - Text - faay_avarage_labour_time_(mh/m2): 0.46; faay_fire_resistance_rating: >60 min. WBDBO; faay_heat_insulation_(Rc): 0.65; faay_sound_insulation_(DnTak): 34; faay_sound_insulation_(Rw): 35; faay_weight_(kg/m2): 49.72
Constraints - Base Constraint: Level: faay_bottom_view_color; Base Extension Distance: 0 mm; Base is Attached: no; Base Offset: 0 mm; Location Line: Wall Centerline; Related to Mass: no; Room Bounding: yes; Top Extension Distance: 0 mm; Top is Attached: no; Top Offset: 0 mm; Unconnected Height: 2605 mm
Dimensions - Area: 7.815 m2; Length: 3000 mm; Volume: 0.617385 m3
Other - Family: Basic Wall: Faay_22_VP54_12.5_2_WR2x; Family and Type: Basic Wall: Faay_22_VP54_12.5_2_WR2x; Type: Basic Wall: Faay_22_VP54_12.5_2_WR2x; Type Id: Basic Wall: Faay_22_VP54_12.5_2_WR2x
Phasing - Phase Created: New Construction
Structural - Enable Analytical Model: no; Structural: no; Structural Usage: Non-bearing
Pset_WallCommon - LoadBearing: no; ExtendToStructure: no; IsExternal: yes; Reference: Faay_22_VP54_12.5_2_WR2x
Pset_ManufacturerTypeInformation - Manufacturer: Faay Vianen B.V.

# IfcWallStandardCase: Basic Wall:Faay_22_VP54_V1x, Basic Wall:Faay_22_VP54_V1x:177174
In: faay_bottom_view_color
Type - PredefinedType: STANDARD; Material: faay_gypsum 10 mm, faay_flax 34 mm, faay_gypsum 10 mm
Type - Analytical Properties - Roughness: 1; Absorptance: 0.1
Type - Construction - Function: Exterior; Wrapping at Inserts: Do not wrap; Width: 54 mm
Type - Graphics - Coarse Scale Fill Color: 0
Type - Identity Data - Manufacturer: Faay Vianen B.V.; Model: Faay_22_VP54_V1x; Type Name: Faay_22_VP54_V1x; URL: http://http://www.faay.nl
Type - Other - Category: Walls; Family Name: Basic Wall
Type - Text - faay_avarage_labour_time_(mh/m2): 0.20; faay_fire_resistance_rating: EI30; faay_heat_insulation_(Rc): 0.42; faay_sound_insulation_(DnTak): 29; faay_sound_insulation_(Rw): 30; faay_weight_(kg/m2): 28.12
Constraints - Base Constraint: Level: faay_bottom_view_color; Base Extension Distance: 0 mm; Base is Attached: no; Base Offset: 0 mm; Location Line: Wall Centerline; Related to Mass: no; Room Bounding: yes; Top Extension Distance: 0 mm; Top is Attached: no; Top Offset: 0 mm; Unconnected Height: 2605 mm
Dimensions - Area: 7.815 m2; Length: 3000 mm; Volume: 0.42201 m3
Other - Family: Basic Wall: Faay_22_VP54_V1x; Family and Type: Basic Wall: Faay_22_VP54_V1x; Type: Basic Wall: Faay_22_VP54_V1x; Type Id: Basic Wall: Faay_22_VP54_V1x
Phasing - Phase Created: New Construction
Structural - Enable Analytical Model: no; Structural: no; Structural Usage: Non-bearing
Pset_WallCommon - LoadBearing: no; ExtendToStructure: no; IsExternal: yes; Reference: Faay_22_VP54_V1x
Pset_ManufacturerTypeInformation - Manufacturer: Faay Vianen B.V.

# IfcWallStandardCase: Basic Wall:Faay_22_VP54_V1x_WR1x_B, Basic Wall:Faay_22_VP54_V1x_WR1x_B:177176
In: faay_bottom_view_color
Type - PredefinedType: STANDARD; Material: faay_gypsum_WR 10 mm, faay_flax 34 mm, faay_gypsum 10 mm
Type - Analytical Properties - Roughness: 1; Absorptance: 0.1
Type - Construction - Function: Exterior; Wrapping at Inserts: Do not wrap; Width: 54 mm
Type - Graphics - Coarse Scale Fill Color: 0
Type - Identity Data - Manufacturer: Faay Vianen B.V.; Model: Faay_22_VP54_V1x_WR1x_B; Type Name: Faay_22_VP54_V1x_WR1x_B; URL: http://http://www.faay.nl
Type - Other - Category: Walls; Family Name: Basic Wall
Type - Text - faay_avarage_labour_time_(mh/m2): 0.20; faay_fire_resistance_rating: EI30; faay_heat_insulation_(Rc): 0.42; faay_sound_insulation_(DnTak): 29; faay_sound_insulation_(Rw): 30; faay_weight_(kg/m2): 28.12
Constraints - Base Constraint: Level: faay_bottom_view_color; Base Extension Distance: 0 mm; Base is Attached: no; Base Offset: 0 mm; Location Line: Wall Centerline; Related to Mass: no; Room Bounding: yes; Top Extension Distance: 0 mm; Top is Attached: no; Top Offset: 0 mm; Unconnected Height: 2605 mm
Dimensions - Area: 7.815 m2; Length: 3000 mm; Volume: 0.42201 m3
Other - Family: Basic Wall: Faay_22_VP54_V1x_WR1x_B; Family and Type: Basic Wall: Faay_22_VP54_V1x_WR1x_B; Type: Basic Wall: Faay_22_VP54_V1x_WR1x_B; Type Id: Basic Wall: Faay_22_VP54_V1x_WR1x_B
Phasing - Phase Created: New Construction
Structural - Enable Analytical Model: no; Structural: no; Structural Usage: Non-bearing
Pset_WallCommon - LoadBearing: no; ExtendToStructure: no; IsExternal: yes; Reference: Faay_22_VP54_V1x_WR1x_B
Pset_ManufacturerTypeInformation - Manufacturer: Faay Vianen B.V.

# IfcWallStandardCase: Basic Wall:Faay_22_VP54_V1x_WR1x_F, Basic Wall:Faay_22_VP54_V1x_WR1x_F:816721
In: faay_bottom_view_color
Type - PredefinedType: STANDARD; Material: faay_gypsum 10 mm, faay_flax 34 mm, faay_gypsum_WR 10 mm
Type - Analytical Properties - Roughness: 1; Absorptance: 0.1
Type - Construction - Function: Exterior; Wrapping at Inserts: Do not wrap; Width: 54 mm
Type - Graphics - Coarse Scale Fill Color: 0
Type - Identity Data - Manufacturer: Faay Vianen B.V.; Model: Faay_22_VP54_V1x_WR1x_F; Type Name: Faay_22_VP54_V1x_WR1x_F; URL: http://http://www.faay.nl
Type - Other - Category: Walls; Family Name: Basic Wall
Type - Text - faay_avarage_labour_time_(mh/m2): 0.20; faay_fire_resistance_rating: EI30; faay_heat_insulation_(Rc): 0.42; faay_sound_insulation_(DnTak): 29; faay_sound_insulation_(Rw): 30; faay_weight_(kg/m2): 28.12
Constraints - Base Constraint: Level: faay_bottom_view_color; Base Extension Distance: 0 mm; Base is Attached: no; Base Offset: 0 mm; Location Line: Wall Centerline; Related to Mass: no; Room Bounding: yes; Top Extension Distance: 0 mm; Top is Attached: no; Top Offset: 0 mm; Unconnected Height: 2605 mm
Dimensions - Area: 7.815 m2; Length: 3000 mm; Volume: 0.42201 m3
Other - Family: Basic Wall: Faay_22_VP54_V1x_WR1x_F; Family and Type: Basic Wall: Faay_22_VP54_V1x_WR1x_F; Type: Basic Wall: Faay_22_VP54_V1x_WR1x_F; Type Id: Basic Wall: Faay_22_VP54_V1x_WR1x_F
Phasing - Phase Created: New Construction
Structural - Enable Analytical Model: no; Structural: no; Structural Usage: Non-bearing
Pset_WallCommon - LoadBearing: no; ExtendToStructure: no; IsExternal: yes; Reference: Faay_22_VP54_V1x_WR1x_F
Pset_ManufacturerTypeInformation - Manufacturer: Faay Vianen B.V.

# IfcWallStandardCase: Basic Wall:Faay_22_VP54_V2x, Basic Wall:Faay_22_VP54_V2x:177175
In: faay_bottom_view_color
Type - PredefinedType: STANDARD; Material: faay_gypsum 10 mm, faay_flax 34 mm, faay_gypsum 10 mm
Type - Analytical Properties - Roughness: 1; Absorptance: 0.1
Type - Construction - Function: Exterior; Wrapping at Inserts: Do not wrap; Width: 54 mm
Type - Graphics - Coarse Scale Fill Color: 0
Type - Identity Data - Manufacturer: Faay Vianen B.V.; Model: Faay_22_VP54_V2x; Type Name: Faay_22_VP54_V2x; URL: http://http://www.faay.nl
Type - Other - Category: Walls; Family Name: Basic Wall
Type - Text - faay_avarage_labour_time_(mh/m2): 0.20; faay_fire_resistance_rating: EI30; faay_heat_insulation_(Rc): 0.42; faay_sound_insulation_(DnTak): 29; faay_sound_insulation_(Rw): 30; faay_weight_(kg/m2): 28.12
Constraints - Base Constraint: Level: faay_bottom_view_color; Base Extension Distance: 0 mm; Base is Attached: no; Base Offset: 0 mm; Location Line: Wall Centerline; Related to Mass: no; Room Bounding: yes; Top Extension Distance: 0 mm; Top is Attached: no; Top Offset: 0 mm; Unconnected Height: 2605 mm
Dimensions - Area: 7.815 m2; Length: 3000 mm; Volume: 0.42201 m3
Other - Family: Basic Wall: Faay_22_VP54_V2x; Family and Type: Basic Wall: Faay_22_VP54_V2x; Type: Basic Wall: Faay_22_VP54_V2x; Type Id: Basic Wall: Faay_22_VP54_V2x
Phasing - Phase Created: New Construction
Structural - Enable Analytical Model: no; Structural: no; Structural Usage: Non-bearing
Pset_WallCommon - LoadBearing: no; ExtendToStructure: no; IsExternal: yes; Reference: Faay_22_VP54_V2x
Pset_ManufacturerTypeInformation - Manufacturer: Faay Vianen B.V.

# IfcWallStandardCase: Basic Wall:Faay_22_VP54_WR1x_B, Basic Wall:Faay_22_VP54_WR1x_B:816720
In: faay_bottom_view_color
Type - PredefinedType: STANDARD; Material: faay_gypsum_WR 10 mm, faay_flax 34 mm, faay_gypsum 10 mm
Type - Analytical Properties - Roughness: 1; Absorptance: 0.1
Type - Construction - Function: Exterior; Wrapping at Inserts: Do not wrap; Width: 54 mm
Type - Graphics - Coarse Scale Fill Color: 0
Type - Identity Data - Manufacturer: Faay Vianen B.V.; Model: Faay_22_VP54_WR1x_B; Type Name: Faay_22_VP54_WR1x_B; URL: http://http://www.faay.nl
Type - Other - Category: Walls; Family Name: Basic Wall
Type - Text - faay_avarage_labour_time_(mh/m2): 0.20; faay_fire_resistance_rating: EI30; faay_heat_insulation_(Rc): 0.42; faay_sound_insulation_(DnTak): 29; faay_sound_insulation_(Rw): 30; faay_weight_(kg/m2): 28.12
Constraints - Base Constraint: Level: faay_bottom_view_color; Base Extension Distance: 0 mm; Base is Attached: no; Base Offset: 0 mm; Location Line: Wall Centerline; Related to Mass: no; Room Bounding: yes; Top Extension Distance: 0 mm; Top is Attached: no; Top Offset: 0 mm; Unconnected Height: 2605 mm
Dimensions - Area: 7.815 m2; Length: 3000 mm; Volume: 0.42201 m3
Other - Family: Basic Wall: Faay_22_VP54_WR1x_B; Family and Type: Basic Wall: Faay_22_VP54_WR1x_B; Type: Basic Wall: Faay_22_VP54_WR1x_B; Type Id: Basic Wall: Faay_22_VP54_WR1x_B
Phasing - Phase Created: New Construction
Structural - Enable Analytical Model: no; Structural: no; Structural Usage: Non-bearing
Pset_WallCommon - LoadBearing: no; ExtendToStructure: no; IsExternal: yes; Reference: Faay_22_VP54_WR1x_B
Pset_ManufacturerTypeInformation - Manufacturer: Faay Vianen B.V.

# IfcWallStandardCase: Basic Wall:Faay_22_VP54_WR1x_F, Basic Wall:Faay_22_VP54_WR1x_F:177172
In: faay_bottom_view_color
Type - PredefinedType: STANDARD; Material: faay_gypsum 10 mm, faay_flax 34 mm, faay_gypsum_WR 10 mm
Type - Analytical Properties - Roughness: 1; Absorptance: 0.1
Type - Construction - Function: Exterior; Wrapping at Inserts: Do not wrap; Width: 54 mm
Type - Graphics - Coarse Scale Fill Color: 0
Type - Identity Data - Manufacturer: Faay Vianen B.V.; Model: Faay_22_VP54_WR1x_F; Type Name: Faay_22_VP54_WR1x_F; URL: http://http://www.faay.nl
Type - Other - Category: Walls; Family Name: Basic Wall
Type - Text - faay_avarage_labour_time_(mh/m2): 0.20; faay_fire_resistance_rating: EI30; faay_heat_insulation_(Rc): 0.42; faay_sound_insulation_(DnTak): 29; faay_sound_insulation_(Rw): 30; faay_weight_(kg/m2): 28.12
Constraints - Base Constraint: Level: faay_bottom_view_color; Base Extension Distance: 0 mm; Base is Attached: no; Base Offset: 0 mm; Location Line: Wall Centerline; Related to Mass: no; Room Bounding: yes; Top Extension Distance: 0 mm; Top is Attached: no; Top Offset: 0 mm; Unconnected Height: 2605 mm
Dimensions - Area: 7.815 m2; Length: 3000 mm; Volume: 0.42201 m3
Other - Family: Basic Wall: Faay_22_VP54_WR1x_F; Family and Type: Basic Wall: Faay_22_VP54_WR1x_F; Type: Basic Wall: Faay_22_VP54_WR1x_F; Type Id: Basic Wall: Faay_22_VP54_WR1x_F
Phasing - Phase Created: New Construction
Structural - Enable Analytical Model: no; Structural: no; Structural Usage: Non-bearing
Pset_WallCommon - LoadBearing: no; ExtendToStructure: no; IsExternal: yes; Reference: Faay_22_VP54_WR1x_F
Pset_ManufacturerTypeInformation - Manufacturer: Faay Vianen B.V.

# IfcWallStandardCase: Basic Wall:Faay_22_VP54_WR2x, Basic Wall:Faay_22_VP54_WR2x:177171
In: faay_bottom_view_color
Type - PredefinedType: STANDARD; Material: faay_gypsum_WR 10 mm, faay_flax 34 mm, faay_gypsum_WR 10 mm
Type - Analytical Properties - Absorptance: 0.1; Roughness: 1
Type - Construction - Function: Exterior; Width: 54 mm; Wrapping at Inserts: Do not wrap
Type - Graphics - Coarse Scale Fill Color: 0
Type - Identity Data - Manufacturer: Faay Vianen B.V.; Model: Faay_22_VP54_WR2x; Type Name: Faay_22_VP54_WR2x; URL: http://http://www.faay.nl
Type - Other - Category: Walls; Family Name: Basic Wall
Type - Text - faay_avarage_labour_time_(mh/m2): 0.20; faay_fire_resistance_rating: EI30; faay_heat_insulation_(Rc): 0.42; faay_sound_insulation_(DnTak): 29; faay_sound_insulation_(Rw): 30; faay_weight_(kg/m2): 28.12
Constraints - Base Constraint: Level: faay_bottom_view_color; Base Extension Distance: 0 mm; Base is Attached: no; Base Offset: 0 mm; Location Line: Wall Centerline; Related to Mass: no; Room Bounding: yes; Top Extension Distance: 0 mm; Top is Attached: no; Top Offset: 0 mm; Unconnected Height: 2605 mm
Dimensions - Area: 7.815 m2; Length: 3000 mm; Volume: 0.42201 m3
Other - Family: Basic Wall: Faay_22_VP54_WR2x; Family and Type: Basic Wall: Faay_22_VP54_WR2x; Type: Basic Wall: Faay_22_VP54_WR2x; Type Id: Basic Wall: Faay_22_VP54_WR2x
Phasing - Phase Created: New Construction
Structural - Enable Analytical Model: no; Structural: no; Structural Usage: Non-bearing
Pset_WallCommon - Reference: Faay_22_VP54_WR2x; LoadBearing: no; ExtendToStructure: no; IsExternal: yes
Pset_ManufacturerTypeInformation - Manufacturer: Faay Vianen B.V.
